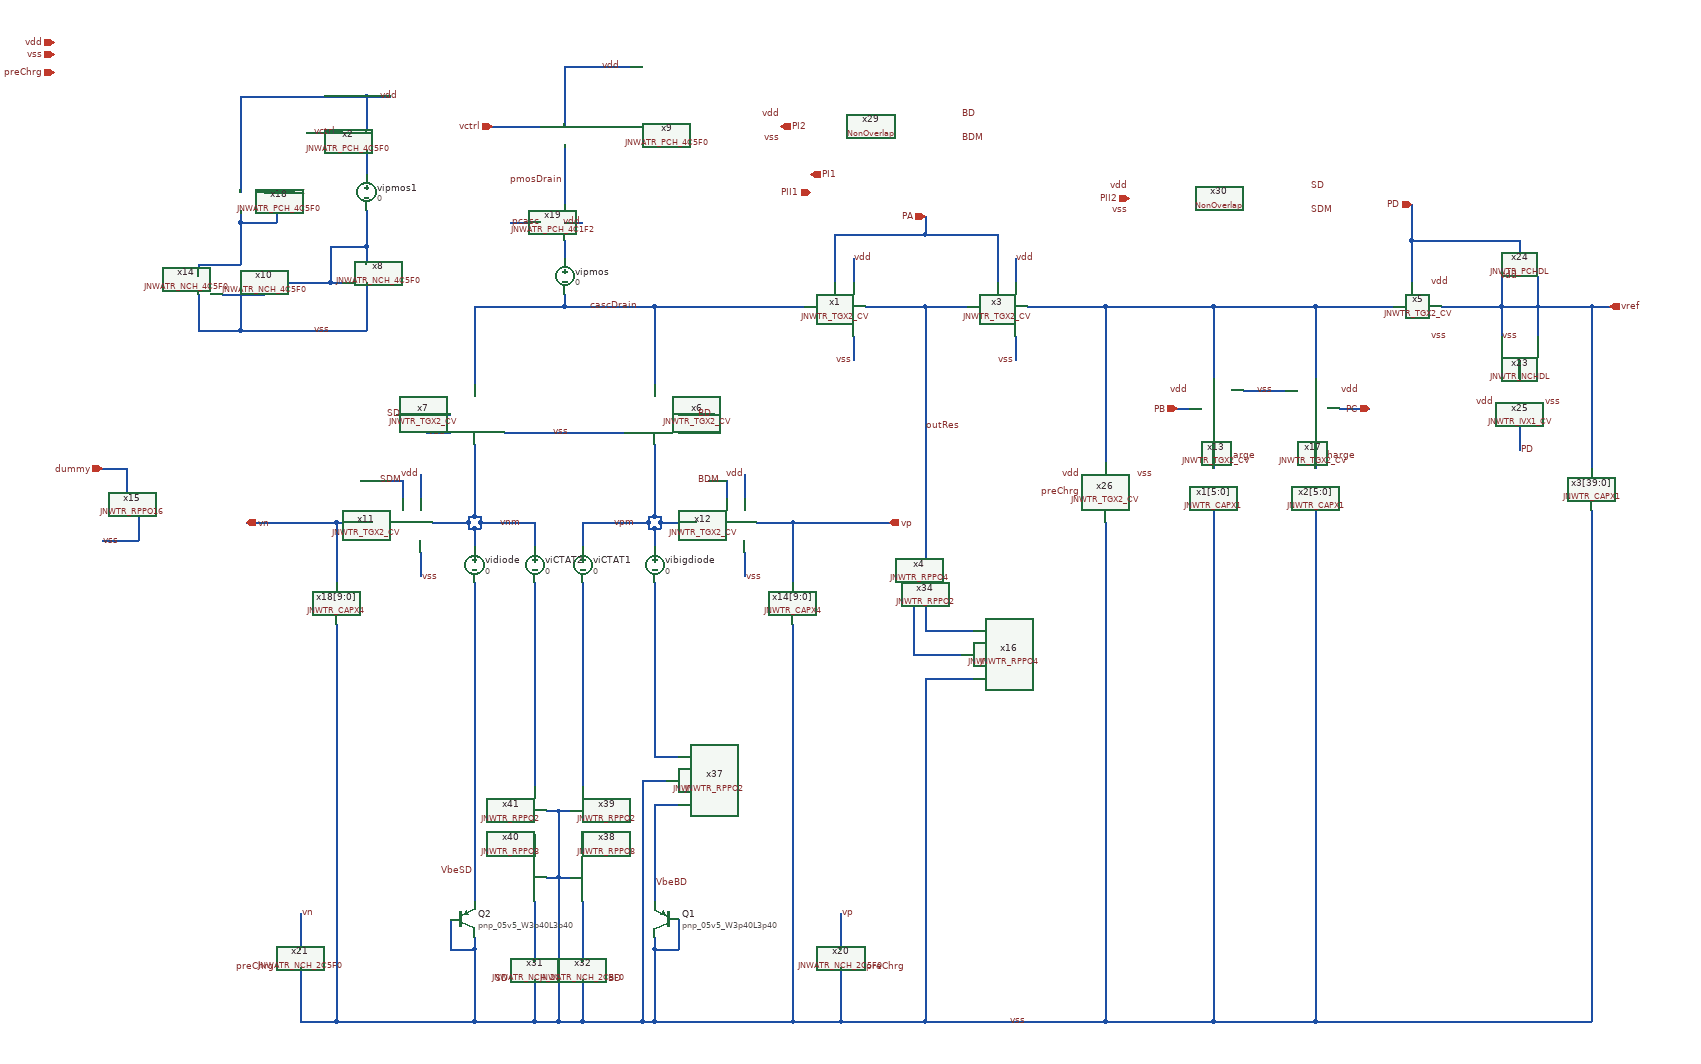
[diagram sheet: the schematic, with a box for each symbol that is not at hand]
v {xschem version=3.4.6 file_version=1.2}
G {}
K {}
V {}
S {}
E {}
N 1270 -1490 1270 -1450 {
lab=vss}
N 1270 -1620 1270 -1580 {
lab=vdd}
N 1240 -1660 1240 -1580 {
lab=PA}
N 1540 -1490 1540 -1450 {
lab=vss}
N 1540 -1620 1540 -1580 {
lab=vdd}
N 1510 -1660 1510 -1580 {
lab=PA}
N 1810 -1370 1830 -1370 {
lab=PB}
N 2080 -1370 2130 -1370 {
lab=PC}
N 2200 -1650 2200 -1580 {
lab=PD}
N 2500 -1540 2500 -1270 {
lab=vref}
N 560 -1330 600 -1330 {
lab=vdd}
N 980 -1360 1040 -1360 {
lab=BD}
N 980 -1330 1020 -1330 {
lab=vdd}
N 690 -1330 890 -1330 {
lab=vss}
N 930 -1180 930 -1170 {
lab=vpm}
N 940 -1190 950 -1190 {
lab=vpm}
N 650 -1180 650 -1170 {
lab=vnm}
N 640 -1190 650 -1190 {
lab=vnm}
N 950 -1180 950 -1170 {
lab=vpm}
N 1390 -920 1390 -350 {
lab=vss}
N 650 -1190 650 -1180 {
lab=vnm}
N 930 -1190 930 -1180 {
lab=vpm}
N 640 -1170 650 -1170 {
lab=vnm}
N 650 -1180 740 -1180 {
lab=vnm}
N 410 -1180 410 -1080 {
lab=vn}
N 630 -1180 630 -1170 {
lab=vnm}
N 410 -1010 410 -350 {
lab=vss}
N 2040 -350 2500 -350 {
lab=vss}
N 2500 -1200 2500 -350 {
lab=vss}
N 2040 -1200 2040 -350 {
lab=vss}
N 1870 -350 2040 -350 {
lab=vss}
N 1870 -1200 1870 -350 {
lab=vss}
N 1690 -350 1870 -350 {
lab=vss}
N 1170 -1010 1170 -350 {
lab=vss}
N 1390 -350 1690 -350 {
lab=vss}
N 600 -520 600 -470 {
lab=vss}
N 600 -470 640 -470 {
lab=vss}
N 980 -520 980 -470 {
lab=vss}
N 940 -470 980 -470 {
lab=vss}
N 940 -490 940 -470 {
lab=vss}
N 1090 -1130 1090 -1090 {
lab=vss}
N 550 -1130 550 -1090 {
lab=vss}
N 1090 -1260 1090 -1220 {
lab=vdd}
N 550 -1260 550 -1220 {
lab=vdd}
N 670 -1840 750 -1840 {
lab=vctrl}
N 790 -1940 790 -1840 {
lab=vdd}
N 520 -1250 520 -1220 {
lab=SDM}
N 450 -1250 520 -1250 {
lab=SDM}
N 1030 -1250 1060 -1250 {
lab=BDM}
N 2500 -1540 2530 -1540 {
lab=vref}
N 1390 -1660 1510 -1660 {
lab=PA}
N 1390 -1690 1390 -1660 {
lab=PA}
N 1240 -1660 1390 -1660 {
lab=PA}
N 510 -1360 600 -1360 {
lab=SD}
N 20 -1270 60 -1270 {
lab=dummy}
N 60 -1270 60 -1230 {
lab=dummy}
N 80 -1190 80 -1150 {
lab=vss}
N 20 -1150 80 -1150 {
lab=vss}
N 640 -490 640 -470 {
lab=vss}
N 940 -1170 950 -1170 {
lab=vpm}
N 790 -1560 790 -1540 {
lab=cascDrain}
N 640 -1540 790 -1540 {
lab=cascDrain}
N 940 -1170 940 -1140 {
lab=vpm}
N 930 -1170 940 -1170 {
lab=vpm}
N 780 -590 780 -350 {
lab=vss}
N 940 -1080 940 -790 {
lab=#net1}
N 940 -1540 1190 -1540 {
lab=cascDrain}
N 640 -1540 640 -1410 {
lab=cascDrain}
N 940 -1540 940 -1410 {
lab=cascDrain}
N 790 -1540 940 -1540 {
lab=cascDrain}
N 940 -1310 940 -1190 {
lab=vpm}
N 930 -1190 940 -1190 {
lab=vpm}
N 950 -1180 1010 -1180 {
lab=vpm}
N 950 -1190 950 -1180 {
lab=vpm}
N 630 -1190 630 -1180 {
lab=vnm}
N 640 -1310 640 -1190 {
lab=vnm}
N 630 -1190 640 -1190 {
lab=vnm}
N 410 -1180 470 -1180 {
lab=vn}
N 1060 -1250 1060 -1220 {
lab=BDM}
N 1870 -1540 1870 -1420 {
lab=#net2}
N 1690 -1540 1870 -1540 {
lab=#net2}
N 1870 -1320 1870 -1270 {
lab=Hcharge}
N 2040 -1540 2040 -1420 {
lab=#net2}
N 1870 -1540 2040 -1540 {
lab=#net2}
N 2040 -1320 2040 -1270 {
lab=Lcharge}
N 1920 -1400 1990 -1400 {
lab=vss}
N 2380 -1650 2380 -1630 {
lab=PD}
N 2200 -1650 2380 -1650 {
lab=PD}
N 2200 -1710 2200 -1650 {
lab=PD}
N 2350 -1590 2350 -1540 {
lab=vref}
N 2250 -1540 2350 -1540 {
lab=vref}
N 2410 -1590 2410 -1540 {
lab=vref}
N 2350 -1540 2410 -1540 {
lab=vref}
N 2380 -1340 2380 -1300 {
lab=PD}
N 2350 -1540 2350 -1490 {
lab=vref}
N 2410 -1540 2410 -1490 {
lab=vref}
N 2410 -1540 2500 -1540 {
lab=vref}
N 2380 -1450 2380 -1420 {
lab=#net3}
N 2040 -1540 2170 -1540 {
lab=#net2}
N 820 -1080 820 -740 {
lab=#net4}
N 740 -1080 740 -740 {
lab=#net5}
N 740 -1180 740 -1140 {
lab=vnm}
N 820 -1180 820 -1140 {
lab=vpm}
N 640 -1170 640 -1140 {
lab=vnm}
N 630 -1170 640 -1170 {
lab=vnm}
N 1690 -1540 1690 -1280 {
lab=#net2}
N 1560 -1540 1690 -1540 {
lab=#net2}
N 1390 -1540 1460 -1540 {
lab=outRes}
N 1250 -350 1390 -350 {
lab=vss}
N 1250 -530 1250 -470 {
lab=vp}
N 1170 -350 1250 -350 {
lab=vss}
N 350 -530 350 -470 {
lab=vn}
N 350 -350 410 -350 {
lab=vss}
N 350 -440 350 -350 {
lab=vss}
N 1250 -440 1250 -350 {
lab=vss}
N 1170 -1180 1170 -1080 {
lab=vp}
N 1110 -1180 1170 -1180 {
lab=vp}
N 640 -470 640 -350 {
lab=vss}
N 410 -350 640 -350 {
lab=vss}
N 940 -350 1170 -350 {
lab=vss}
N 940 -470 940 -350 {
lab=vss}
N 920 -750 920 -350 {
lab=vss}
N 940 -710 940 -550 {
lab=VbeBD}
N 640 -1080 640 -550 {
lab=VbeSD}
N 920 -350 940 -350 {
lab=vss}
N 820 -1180 930 -1180 {
lab=vpm}
N 570 -1180 630 -1180 {
lab=vnm}
N 740 -350 780 -350 {
lab=vss}
N 820 -350 920 -350 {
lab=vss}
N 820 -550 820 -450 {lab=#net6}
N 820 -420 820 -350 {lab=vss}
N 780 -350 820 -350 {
lab=vss}
N 740 -420 740 -350 {lab=vss}
N 640 -350 740 -350 {
lab=vss}
N 740 -550 740 -450 {lab=#net7}
N 1370 -1080 1370 -960 {lab=#net8}
N 920 -750 960 -750 {lab=vss}
N 940 -790 980 -790 {lab=#net1}
N 940 -710 980 -710 {lab=VbeBD}
N 780 -590 800 -590 {lab=vss}
N 820 -660 820 -630 {lab=#net9}
N 740 -660 740 -630 {lab=#net10}
N 760 -590 780 -590 {lab=vss}
N 780 -700 800 -700 {lab=vss}
N 780 -700 780 -590 {lab=vss}
N 760 -700 780 -700 {lab=vss}
N 1690 -1180 1690 -350 {
lab=vss}
N 1390 -1040 1390 -1000 {lab=#net11}
N 1390 -1540 1390 -1120 {lab=outRes}
N 1290 -1540 1390 -1540 {
lab=outRes}
N 460 -1890 460 -1830 {lab=vdd}
N 460 -1890 500 -1890 {lab=vdd}
N 460 -1640 460 -1610 {lab=#net12}
N 360 -1830 420 -1830 {lab=vctrl}
N 460 -1580 460 -1500 {lab=vss}
N 400 -1580 420 -1580 {lab=#net12}
N 250 -1580 250 -1500 {lab=vss}
N 250 -1680 250 -1610 {lab=pcasc}
N 250 -1890 250 -1730 {lab=vdd}
N 250 -1890 460 -1890 {lab=vdd}
N 310 -1730 340 -1730 {lab=pcasc}
N 400 -1640 460 -1640 {lab=#net12}
N 460 -1700 460 -1640 {lab=#net12}
N 400 -1640 400 -1580 {lab=#net12}
N 290 -1580 400 -1580 {lab=#net12}
N 310 -1730 310 -1680 {lab=pcasc}
N 250 -1680 310 -1680 {lab=pcasc}
N 290 -1730 310 -1730 {lab=pcasc}
N 250 -1700 250 -1680 {lab=pcasc}
N 790 -1680 820 -1680 {lab=vdd}
N 700 -1680 750 -1680 {lab=pcasc}
N 460 -1800 460 -1760 {lab=#net13}
N 250 -1500 460 -1500 {lab=vss}
N 220 -1560 290 -1560 {lab=#net12}
N 290 -1580 290 -1560 {lab=#net12}
N 180 -1500 250 -1500 {lab=vss}
N 180 -1560 180 -1500 {lab=vss}
N 180 -1610 180 -1590 {lab=pcasc}
N 180 -1610 250 -1610 {lab=pcasc}
N 1390 -1000 1470 -1000 {lab=#net11}
N 1370 -960 1450 -960 {lab=#net8}
N 1390 -920 1470 -920 {lab=vss}
N 790 -1650 790 -1620 {lab=#net14}
N 1170 -1180 1330 -1180 {lab=vp}
N 260 -1180 410 -1180 {lab=vn}
N 790 -1940 900 -1940 {
lab=vdd}
N 790 -1810 790 -1710 {lab=pmosDrain}
C {devices/ipin.sym} -60 -1980 0 0 {name=p1 lab=vdd}
C {devices/ipin.sym} -60 -1960 0 0 {name=p2 lab=vss
}
C {devices/lab_wire.sym} 1560 -350 0 0 {name=p4 sig_type=std_logic lab=vss
}
C {devices/lab_wire.sym} 1270 -1450 0 0 {name=p5 sig_type=std_logic lab=vss
}
C {devices/lab_wire.sym} 1270 -1620 0 1 {name=p6 sig_type=std_logic lab=vdd

}
C {devices/lab_wire.sym} 1540 -1450 0 0 {name=p9 sig_type=std_logic lab=vss
}
C {devices/lab_wire.sym} 1540 -1620 0 1 {name=p11 sig_type=std_logic lab=vdd

}
C {devices/lab_wire.sym} 1830 -1400 0 0 {name=p12 sig_type=std_logic lab=vdd

}
C {devices/lab_wire.sym} 2080 -1400 0 1 {name=p13 sig_type=std_logic lab=vdd

}
C {devices/lab_wire.sym} 2230 -1580 0 1 {name=p17 sig_type=std_logic lab=vdd

}
C {devices/lab_wire.sym} 800 -1330 0 0 {name=p18 sig_type=std_logic lab=vss
}
C {devices/lab_wire.sym} 560 -1330 0 1 {name=p19 sig_type=std_logic lab=vdd

}
C {devices/lab_wire.sym} 1020 -1330 0 0 {name=p20 sig_type=std_logic lab=vdd

}
C {JNW_TR_SKY130A/JNWTR_CAPX4.sym} 1170 -1020 0 0 {name=x14[9:0]}
C {JNW_TR_SKY130A/JNWTR_CAPX4.sym} 410 -1020 0 1 {name=x18[9:0]}
C {sky130_fd_pr/pnp_05v5.sym} 960 -520 0 1 {name=Q1
model=pnp_05v5_W3p40L3p40
m=8
spiceprefix=X
}
C {sky130_fd_pr/pnp_05v5.sym} 620 -520 0 0 {name=Q2
model=pnp_05v5_W3p40L3p40
m=1
spiceprefix=X
}
C {devices/lab_wire.sym} 1090 -1090 0 1 {name=p23 sig_type=std_logic lab=vss
}
C {devices/lab_wire.sym} 550 -1090 0 1 {name=p24 sig_type=std_logic lab=vss
}
C {devices/lab_wire.sym} 1090 -1260 0 0 {name=p25 sig_type=std_logic lab=vdd

}
C {devices/lab_wire.sym} 550 -1260 0 0 {name=p26 sig_type=std_logic lab=vdd

}
C {devices/ipin.sym} 670 -1840 0 0 {name=p27 lab=vctrl}
C {devices/ipin.sym} 2200 -1710 1 0 {name=p8 lab=PD}
C {devices/ipin.sym} 1810 -1370 0 0 {name=p10 lab=PB}
C {devices/ipin.sym} 2130 -1370 2 0 {name=p15 lab=PC}
C {devices/ipin.sym} 1390 -1690 1 0 {name=p16 lab=PA}
C {devices/ipin.sym} 1150 -1840 2 1 {name=p31 lab=PI2}
C {devices/ipin.sym} 20 -1270 0 0 {name=p32 lab=dummy}
C {devices/opin.sym} 2530 -1540 0 0 {name=p3 lab=vref}
C {devices/opin.sym} 1330 -1180 0 0 {name=p21 lab=vp}
C {devices/opin.sym} 260 -1180 2 0 {name=p22 lab=vn}
C {devices/ipin.sym} 1730 -1720 0 0 {name=p29 lab=PII2}
C {devices/lab_wire.sym} 20 -1150 0 1 {name=p30 sig_type=std_logic lab=vss
}
C {JNW_TR_SKY130A/JNWTR_CAPX1.sym} 1870 -1210 0 0 {name=x1[5:0]}
C {JNW_TR_SKY130A/JNWTR_CAPX1.sym} 2040 -1210 0 0 {name=x2[5:0]}
C {JNW_TR_SKY130A/JNWTR_CAPX1.sym} 2500 -1210 0 0 {name=x3[39:0]}
C {JNW_ATR_SKY130A/JNWATR_PCH_4C5F0.sym} 750 -1840 0 0 {name=x9 }
C {devices/vsource.sym} 790 -1590 0 0 {name=vipmos value=0 savecurrent=true}
C {devices/vsource.sym} 940 -1110 0 0 {name=vibigdiode value=0 savecurrent=true}
C {devices/lab_wire.sym} 1870 -1290 0 1 {name=p35 sig_type=std_logic lab=Hcharge

}
C {devices/lab_wire.sym} 2040 -1290 0 1 {name=p36 sig_type=std_logic lab=Lcharge

}
C {devices/lab_wire.sym} 1390 -1340 0 1 {name=p37 sig_type=std_logic lab=outRes

}
C {JNW_TR_SKY130A/JNWTR_TGX2_CV.sym} 1180 -1540 0 0 {name=x1 }
C {JNW_TR_SKY130A/JNWTR_TGX2_CV.sym} 1450 -1540 0 0 {name=x3 }
C {JNW_TR_SKY130A/JNWTR_TGX2_CV.sym} 940 -1420 1 0 {name=x6 }
C {JNW_TR_SKY130A/JNWTR_TGX2_CV.sym} 640 -1420 3 1 {name=x7 }
C {JNW_TR_SKY130A/JNWTR_TGX2_CV.sym} 460 -1180 0 0 {name=x11 }
C {JNW_TR_SKY130A/JNWTR_TGX2_CV.sym} 1000 -1180 0 0 {name=x12 }
C {devices/lab_wire.sym} 2230 -1490 0 1 {name=p42 sig_type=std_logic lab=vss
}
C {devices/lab_wire.sym} 1940 -1400 0 1 {name=p38 sig_type=std_logic lab=vss
}
C {JNW_TR_SKY130A/JNWTR_TGX2_CV.sym} 2140 -1540 0 0 {name=x5 }
C {JNW_TR_SKY130A/JNWTR_TGX2_CV.sym} 1870 -1310 3 0 {name=x13 }
C {JNW_TR_SKY130A/JNWTR_TGX2_CV.sym} 2040 -1310 1 1 {name=x17 }
C {JNW_TR_SKY130A/JNWTR_NCHDL.sym} 2380 -1450 3 0 {name=x23 }
C {JNW_TR_SKY130A/JNWTR_PCHDL.sym} 2380 -1630 1 0 {name=x24 }
C {JNW_TR_SKY130A/JNWTR_IVX1_CV.sym} 2380 -1340 3 0 {name=x25 }
C {devices/lab_wire.sym} 2380 -1300 0 1 {name=p7 sig_type=std_logic lab=PD

}
C {devices/lab_wire.sym} 2340 -1380 0 0 {name=p14 sig_type=std_logic lab=vdd

}
C {devices/lab_wire.sym} 2380 -1590 1 1 {name=p39 sig_type=std_logic lab=vdd

}
C {devices/lab_wire.sym} 2380 -1490 1 0 {name=p40 sig_type=std_logic lab=vss
}
C {devices/lab_wire.sym} 2420 -1380 0 1 {name=p41 sig_type=std_logic lab=vss
}
C {JNW_TR_SKY130A/JNWTR_RPPO16.sym} 60 -1230 3 1 {name=x15 }
C {devices/lab_wire.sym} 830 -1540 0 1 {name=p43 sig_type=std_logic lab=cascDrain

}
C {devices/vsource.sym} 820 -1110 0 0 {name=viCTAT1 value=0 savecurrent=true}
C {devices/lab_wire.sym} 640 -600 0 0 {name=p44 sig_type=std_logic lab=VbeSD

}
C {devices/vsource.sym} 740 -1110 0 0 {name=viCTAT2 value=0 savecurrent=true}
C {devices/vsource.sym} 640 -1110 0 0 {name=vidiode value=0 savecurrent=true}
C {devices/lab_wire.sym} 940 -580 0 1 {name=p45 sig_type=std_logic lab=VbeBD

}
C {JNW_TR_SKY130A/JNWTR_TGX2_CV.sym} 1690 -1170 3 0 {name=x26 }
C {devices/lab_wire.sym} 1650 -1260 0 0 {name=p46 sig_type=std_logic lab=vdd

}
C {devices/lab_wire.sym} 1740 -1260 0 1 {name=p47 sig_type=std_logic lab=vss
}
C {devices/lab_wire.sym} 350 -530 0 1 {name=p55 sig_type=std_logic lab=vn

}
C {devices/lab_wire.sym} 1250 -530 0 1 {name=p56 sig_type=std_logic lab=vp

}
C {devices/ipin.sym} -60 -1930 0 0 {name=p57 lab=preChrg}
C {devices/lab_wire.sym} 1650 -1230 0 0 {name=p48 sig_type=std_logic lab=preChrg

}
C {devices/lab_wire.sym} 310 -440 0 0 {name=p51 sig_type=std_logic lab=preChrg

}
C {devices/lab_wire.sym} 1290 -440 0 1 {name=p54 sig_type=std_logic lab=preChrg

}
C {JNW_AVV_SKY130A/NonOverlap.sym} 1300 -1840 0 0 {name=x29}
C {JNW_AVV_SKY130A/NonOverlap.sym} 1880 -1720 0 0 {name=x30}
C {devices/lab_wire.sym} 1150 -1860 0 0 {name=p49 sig_type=std_logic lab=vdd

}
C {devices/lab_wire.sym} 1150 -1820 2 1 {name=p50 sig_type=std_logic lab=vss
}
C {devices/lab_wire.sym} 1730 -1740 0 0 {name=p52 sig_type=std_logic lab=vdd

}
C {devices/lab_wire.sym} 1730 -1700 2 1 {name=p53 sig_type=std_logic lab=vss
}
C {devices/lab_wire.sym} 1010 -1360 0 1 {name=p59 sig_type=std_logic lab=BD

}
C {devices/lab_wire.sym} 1050 -1250 0 0 {name=p58 sig_type=std_logic lab=BDM

}
C {devices/lab_wire.sym} 520 -1360 0 0 {name=p60 sig_type=std_logic lab=SD

}
C {devices/lab_wire.sym} 480 -1250 0 1 {name=p61 sig_type=std_logic lab=SDM

}
C {devices/lab_wire.sym} 1450 -1860 0 1 {name=p62 sig_type=std_logic lab=BD

}
C {devices/lab_wire.sym} 1450 -1820 0 1 {name=p63 sig_type=std_logic lab=BDM

}
C {devices/lab_wire.sym} 2030 -1740 0 1 {name=p64 sig_type=std_logic lab=SD

}
C {devices/lab_wire.sym} 2030 -1700 0 1 {name=p65 sig_type=std_logic lab=SDM

}
C {devices/lab_wire.sym} 910 -1180 0 0 {name=p66 sig_type=std_logic lab=vpm

}
C {devices/lab_wire.sym} 680 -1180 0 1 {name=p67 sig_type=std_logic lab=vnm

}
C {devices/lab_wire.sym} 790 -1750 0 0 {name=p68 sig_type=std_logic lab=pmosDrain

}
C {devices/lab_wire.sym} 700 -420 0 0 {name=p70 sig_type=std_logic lab=SD

}
C {devices/lab_wire.sym} 860 -420 0 1 {name=p71 sig_type=std_logic lab=BD

}
C {JNW_ATR_SKY130A/JNWATR_NCH_2C5F0.sym} 700 -420 0 0 {name=x31 }
C {JNW_ATR_SKY130A/JNWATR_NCH_2C5F0.sym} 860 -420 0 1 {name=x32 }
C {JNW_TR_SKY130A/JNWTR_RPPO4.sym} 1390 -1120 1 0 {name=x4 }
C {JNW_TR_SKY130A/JNWTR_RPPO2.sym} 1390 -1000 1 0 {name=x34 }
C {JNW_TR_SKY130A/JNWTR_RPPO2.sym} 1430 -1000 1 0 {name=x35 }
C {JNW_TR_SKY130A/JNWTR_RPPO2.sym} 940 -790 1 0 {name=x36 }
C {JNW_TR_SKY130A/JNWTR_RPPO2.sym} 980 -790 1 0 {name=x37 }
C {JNW_TR_SKY130A/JNWTR_RPPO8.sym} 820 -630 1 0 {name=x38 }
C {JNW_TR_SKY130A/JNWTR_RPPO2.sym} 820 -740 1 0 {name=x39 }
C {JNW_TR_SKY130A/JNWTR_RPPO8.sym} 740 -630 3 1 {name=x40 }
C {JNW_TR_SKY130A/JNWTR_RPPO2.sym} 740 -740 3 1 {name=x41 }
C {JNW_ATR_SKY130A/JNWATR_PCH_4C5F0.sym} 420 -1830 0 0 {name=x2 }
C {devices/lab_wire.sym} 480 -1890 0 1 {name=p69 sig_type=std_logic lab=vdd

}
C {devices/lab_wire.sym} 370 -1830 0 1 {name=p72 sig_type=std_logic lab=vctrl

}
C {JNW_ATR_SKY130A/JNWATR_NCH_4C5F0.sym} 420 -1580 0 0 {name=x8 }
C {JNW_ATR_SKY130A/JNWATR_NCH_4C5F0.sym} 290 -1580 0 1 {name=x10 }
C {devices/lab_wire.sym} 310 -1730 0 1 {name=p73 sig_type=std_logic lab=pcasc

}
C {JNW_ATR_SKY130A/JNWATR_PCH_4C5F0.sym} 290 -1730 0 1 {name=x18 }
C {JNW_ATR_SKY130A/JNWATR_PCH_4C1F2.sym} 750 -1680 0 0 {name=x19 }
C {devices/lab_wire.sym} 820 -1680 0 0 {name=p74 sig_type=std_logic lab=vdd

}
C {devices/lab_wire.sym} 700 -1680 0 1 {name=p75 sig_type=std_logic lab=pcasc

}
C {devices/vsource.sym} 460 -1730 0 0 {name=vipmos1 value=0 savecurrent=true}
C {devices/lab_wire.sym} 370 -1500 0 1 {name=p76 sig_type=std_logic lab=vss
}
C {devices/lab_wire.sym} 850 -1940 0 1 {name=p28 sig_type=std_logic lab=vdd

}
C {JNW_ATR_SKY130A/JNWATR_NCH_4C5F0.sym} 220 -1560 0 1 {name=x14 }
C {JNW_TR_SKY130A/JNWTR_RPPO4.sym} 1470 -1000 1 0 {name=x16 }
C {JNW_ATR_SKY130A/JNWATR_NCH_2C5F0.sym} 1290 -440 0 1 {name=x20 }
C {JNW_ATR_SKY130A/JNWATR_NCH_2C5F0.sym} 310 -440 0 0 {name=x21 }
C {devices/ipin.sym} 1200 -1760 2 1 {name=p33 lab=PI1}
C {devices/ipin.sym} 1200 -1730 0 0 {name=p34 lab=PII1}
